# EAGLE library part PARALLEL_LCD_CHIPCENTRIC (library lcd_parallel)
Same as above Except this device has a different symbol which is chip centric... well more like connector-centric. It's the same as the dip header for an lcd.

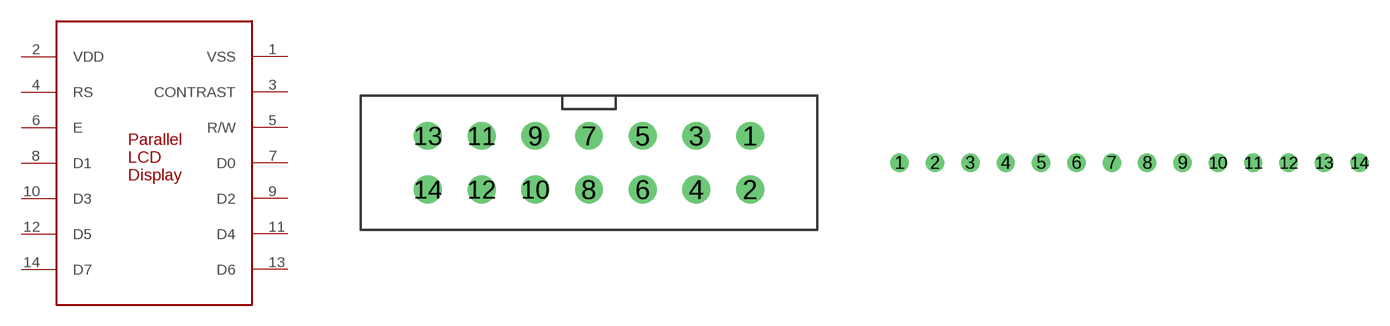
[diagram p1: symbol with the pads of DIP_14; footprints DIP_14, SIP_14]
Designator prefix -

## PARALLEL_LCD_CHIPCENTRICDIP  [DIP_14]
1  VSS
2  VDD
3  CONTRAST
4  RS
5  R/W
6  E
7  D0
8  D1
9  D2
10  D3
11  D4
12  D5
13  D6
14  D7

## PARALLEL_LCD_CHIPCENTRICSIP  [SIP_14]
Pads as for DIP_14

## Footprint DIP_14 (pad centres in mm)
14-Pin Dual In-Line Package This is a very common connector for parallel LCD's. You can buy a variety of LCD's with this connector already attached on parallax.com and usually on goldmine-elec.com.
drill 0.813 round: 1 7.62,1.27; 2 7.62,-1.27; 3 5.08,1.27; 4 5.08,-1.27; 5 2.54,1.27; 6 2.54,-1.27; 7 0,1.27; 8 0,-1.27; 9 -2.54,1.27; 10 -2.54,-1.27; 11 -5.08,1.27; 12 -5.08,-1.27; 13 -7.62,1.27; 14 -7.62,-1.27

## Footprint SIP_14 (pad centres in mm)
14 Pin Single Inline Package typically used when connecting the lcd pcb directly to the pcb you're trying to make with male headers
drill 0.813 round: 1 -15.24,0; 2 -12.7,0; 3 -10.16,0; 4 -7.62,0; 5 -5.08,0; 6 -2.54,0; 7 0,0; 8 2.54,0; 9 5.08,0; 10 7.62,0; 11 10.16,0; 12 12.7,0; 13 15.24,0; 14 17.78,0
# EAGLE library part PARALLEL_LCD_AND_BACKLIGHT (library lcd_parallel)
Backlit Parallel LCD Standard HD44780 LCD type

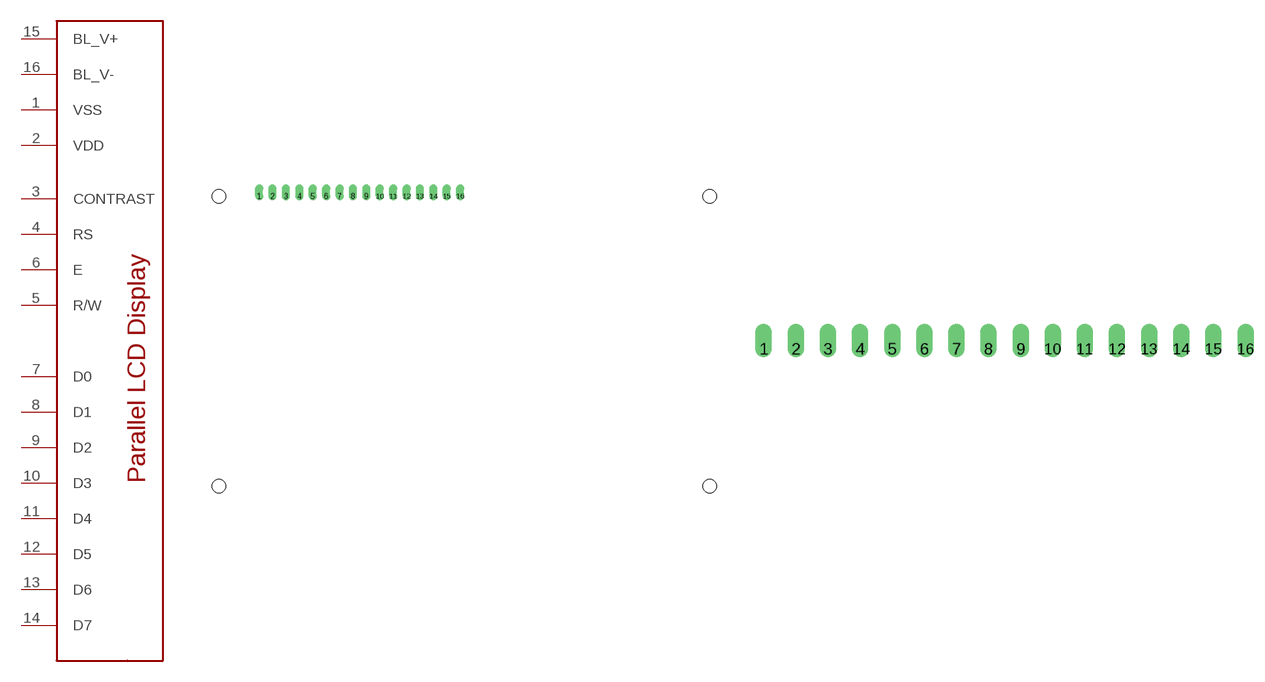
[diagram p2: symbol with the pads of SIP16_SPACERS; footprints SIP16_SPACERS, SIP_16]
Designator prefix LCD

## PARALLEL_LCD_AND_BACKLIGHTSTANDOFFS  [SIP16_SPACERS]
1  VSS
2  VDD
3  CONTRAST
4  RS
5  R/W
6  E
7  D0
8  D1
9  D2
10  D3
11  D4
12  D5
13  D6
14  D7
15  BL_V+
16  BL_V-

## PARALLEL_LCD_AND_BACKLIGHT  [SIP_16]
Pads as for SIP16_SPACERS

## Footprint SIP16_SPACERS (pad centres in mm)
SIP Package SIP layout, 16 Pins. Spacers seperated by 93mm Left to right and 55 mm top to bottom... The particular Model i wrote this package for was Orient Display's OD-DM2004A
drill 1.016 offset: 1 -16.51,-0.889; 2 -13.97,-0.889; 3 -11.43,-0.889; 4 -8.89,-0.889; 5 -6.35,-0.889; 6 -3.81,-0.889; 7 -1.27,-0.889; 8 1.27,-0.889; 9 3.81,-0.889; 10 6.35,-0.889; 11 8.89,-0.889; 12 11.43,-0.889; 13 13.97,-0.889; 14 16.51,-0.889; 15 19.05,-0.889; 16 21.59,-0.889
hole 2.54 at -24.13,-55.88
hole 2.54 at 68.87,-55.88
hole 2.54 at -24.13,-0.88
hole 2.54 at 68.87,-0.88

## Footprint SIP_16 (pad centres in mm)
SIP 16 LCD with backlights Package includes spacing to be used when connecting a ribbon cable to the lcd that isn't going to be mounted directly to the board
drill 0.813 offset: 1 -16.51,0; 2 -13.97,0; 3 -11.43,0; 4 -8.89,0; 5 -6.35,0; 6 -3.81,0; 7 -1.27,0; 8 1.27,0; 9 3.81,0; 10 6.35,0; 11 8.89,0; 12 11.43,0; 13 13.97,0; 14 16.51,0; 15 19.05,0; 16 21.59,0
